VERSION 5.7 ;
BUSBITCHARS "[]" ;
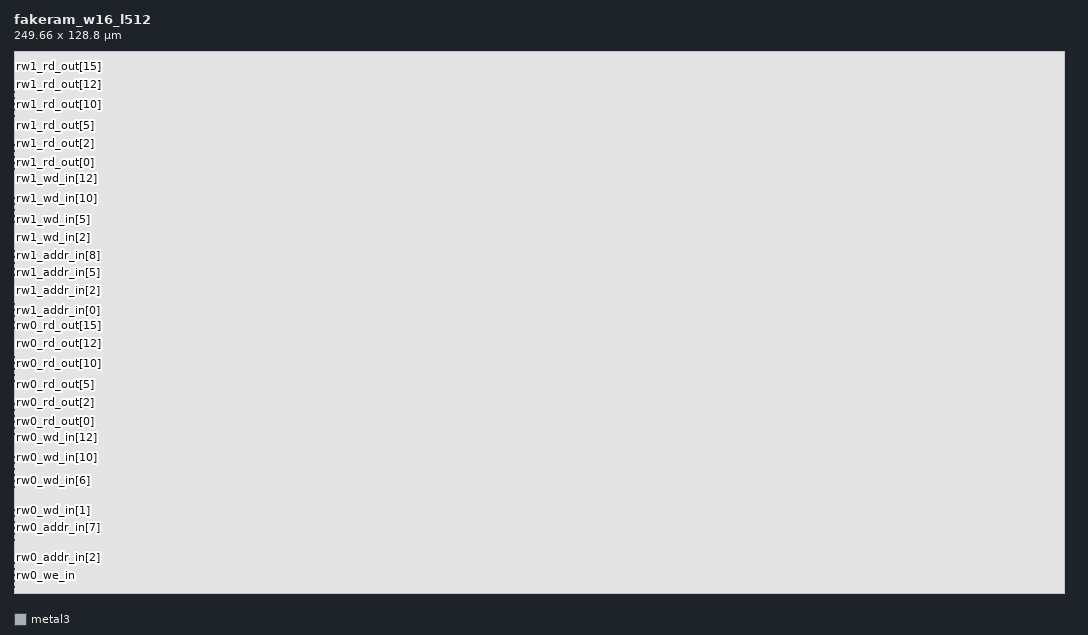
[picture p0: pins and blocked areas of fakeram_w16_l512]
MACRO fakeram_w16_l512
  FOREIGN fakeram_w16_l512 0 0 ;
  SYMMETRY X Y R90 ;
  SIZE 249.660 BY 128.800 ;
  CLASS BLOCK ;
  PIN rw0_clk
    DIRECTION INPUT ;
    USE SIGNAL ;
    SHAPE ABUTMENT ;
    PORT
      LAYER metal3 ;
      RECT 0.000 1.400 0.140 1.540 ;
    END
  END rw0_clk
  PIN rw0_ce_in
    DIRECTION INPUT ;
    USE SIGNAL ;
    SHAPE ABUTMENT ;
    PORT
      LAYER metal3 ;
      RECT 0.000 2.800 0.140 2.940 ;
    END
  END rw0_ce_in
  PIN rw0_we_in
    DIRECTION INPUT ;
    USE SIGNAL ;
    SHAPE ABUTMENT ;
    PORT
      LAYER metal3 ;
      RECT 0.000 4.200 0.140 4.340 ;
    END
  END rw0_we_in
  PIN rw0_addr_in[0]
    DIRECTION INPUT ;
    USE SIGNAL ;
    SHAPE ABUTMENT ;
    PORT
      LAYER metal3 ;
      RECT 0.000 5.600 0.140 5.740 ;
    END
  END rw0_addr_in[0]
  PIN rw0_addr_in[1]
    DIRECTION INPUT ;
    USE SIGNAL ;
    SHAPE ABUTMENT ;
    PORT
      LAYER metal3 ;
      RECT 0.000 7.000 0.140 7.140 ;
    END
  END rw0_addr_in[1]
  PIN rw0_addr_in[2]
    DIRECTION INPUT ;
    USE SIGNAL ;
    SHAPE ABUTMENT ;
    PORT
      LAYER metal3 ;
      RECT 0.000 8.400 0.140 8.540 ;
    END
  END rw0_addr_in[2]
  PIN rw0_addr_in[3]
    DIRECTION INPUT ;
    USE SIGNAL ;
    SHAPE ABUTMENT ;
    PORT
      LAYER metal3 ;
      RECT 0.000 9.800 0.140 9.940 ;
    END
  END rw0_addr_in[3]
  PIN rw0_addr_in[4]
    DIRECTION INPUT ;
    USE SIGNAL ;
    SHAPE ABUTMENT ;
    PORT
      LAYER metal3 ;
      RECT 0.000 11.200 0.140 11.340 ;
    END
  END rw0_addr_in[4]
  PIN rw0_addr_in[5]
    DIRECTION INPUT ;
    USE SIGNAL ;
    SHAPE ABUTMENT ;
    PORT
      LAYER metal3 ;
      RECT 0.000 12.600 0.140 12.740 ;
    END
  END rw0_addr_in[5]
  PIN rw0_addr_in[6]
    DIRECTION INPUT ;
    USE SIGNAL ;
    SHAPE ABUTMENT ;
    PORT
      LAYER metal3 ;
      RECT 0.000 14.000 0.140 14.140 ;
    END
  END rw0_addr_in[6]
  PIN rw0_addr_in[7]
    DIRECTION INPUT ;
    USE SIGNAL ;
    SHAPE ABUTMENT ;
    PORT
      LAYER metal3 ;
      RECT 0.000 15.400 0.140 15.540 ;
    END
  END rw0_addr_in[7]
  PIN rw0_addr_in[8]
    DIRECTION INPUT ;
    USE SIGNAL ;
    SHAPE ABUTMENT ;
    PORT
      LAYER metal3 ;
      RECT 0.000 16.800 0.140 16.940 ;
    END
  END rw0_addr_in[8]
  PIN rw0_wd_in[0]
    DIRECTION INPUT ;
    USE SIGNAL ;
    SHAPE ABUTMENT ;
    PORT
      LAYER metal3 ;
      RECT 0.000 18.200 0.140 18.340 ;
    END
  END rw0_wd_in[0]
  PIN rw0_wd_in[1]
    DIRECTION INPUT ;
    USE SIGNAL ;
    SHAPE ABUTMENT ;
    PORT
      LAYER metal3 ;
      RECT 0.000 19.600 0.140 19.740 ;
    END
  END rw0_wd_in[1]
  PIN rw0_wd_in[2]
    DIRECTION INPUT ;
    USE SIGNAL ;
    SHAPE ABUTMENT ;
    PORT
      LAYER metal3 ;
      RECT 0.000 21.000 0.140 21.140 ;
    END
  END rw0_wd_in[2]
  PIN rw0_wd_in[3]
    DIRECTION INPUT ;
    USE SIGNAL ;
    SHAPE ABUTMENT ;
    PORT
      LAYER metal3 ;
      RECT 0.000 22.400 0.140 22.540 ;
    END
  END rw0_wd_in[3]
  PIN rw0_wd_in[4]
    DIRECTION INPUT ;
    USE SIGNAL ;
    SHAPE ABUTMENT ;
    PORT
      LAYER metal3 ;
      RECT 0.000 23.800 0.140 23.940 ;
    END
  END rw0_wd_in[4]
  PIN rw0_wd_in[5]
    DIRECTION INPUT ;
    USE SIGNAL ;
    SHAPE ABUTMENT ;
    PORT
      LAYER metal3 ;
      RECT 0.000 25.200 0.140 25.340 ;
    END
  END rw0_wd_in[5]
  PIN rw0_wd_in[6]
    DIRECTION INPUT ;
    USE SIGNAL ;
    SHAPE ABUTMENT ;
    PORT
      LAYER metal3 ;
      RECT 0.000 26.600 0.140 26.740 ;
    END
  END rw0_wd_in[6]
  PIN rw0_wd_in[7]
    DIRECTION INPUT ;
    USE SIGNAL ;
    SHAPE ABUTMENT ;
    PORT
      LAYER metal3 ;
      RECT 0.000 28.000 0.140 28.140 ;
    END
  END rw0_wd_in[7]
  PIN rw0_wd_in[8]
    DIRECTION INPUT ;
    USE SIGNAL ;
    SHAPE ABUTMENT ;
    PORT
      LAYER metal3 ;
      RECT 0.000 29.400 0.140 29.540 ;
    END
  END rw0_wd_in[8]
  PIN rw0_wd_in[9]
    DIRECTION INPUT ;
    USE SIGNAL ;
    SHAPE ABUTMENT ;
    PORT
      LAYER metal3 ;
      RECT 0.000 30.800 0.140 30.940 ;
    END
  END rw0_wd_in[9]
  PIN rw0_wd_in[10]
    DIRECTION INPUT ;
    USE SIGNAL ;
    SHAPE ABUTMENT ;
    PORT
      LAYER metal3 ;
      RECT 0.000 32.200 0.140 32.340 ;
    END
  END rw0_wd_in[10]
  PIN rw0_wd_in[11]
    DIRECTION INPUT ;
    USE SIGNAL ;
    SHAPE ABUTMENT ;
    PORT
      LAYER metal3 ;
      RECT 0.000 33.600 0.140 33.740 ;
    END
  END rw0_wd_in[11]
  PIN rw0_wd_in[12]
    DIRECTION INPUT ;
    USE SIGNAL ;
    SHAPE ABUTMENT ;
    PORT
      LAYER metal3 ;
      RECT 0.000 35.000 0.140 35.140 ;
    END
  END rw0_wd_in[12]
  PIN rw0_wd_in[13]
    DIRECTION INPUT ;
    USE SIGNAL ;
    SHAPE ABUTMENT ;
    PORT
      LAYER metal3 ;
      RECT 0.000 36.400 0.140 36.540 ;
    END
  END rw0_wd_in[13]
  PIN rw0_wd_in[14]
    DIRECTION INPUT ;
    USE SIGNAL ;
    SHAPE ABUTMENT ;
    PORT
      LAYER metal3 ;
      RECT 0.000 37.800 0.140 37.940 ;
    END
  END rw0_wd_in[14]
  PIN rw0_wd_in[15]
    DIRECTION INPUT ;
    USE SIGNAL ;
    SHAPE ABUTMENT ;
    PORT
      LAYER metal3 ;
      RECT 0.000 39.200 0.140 39.340 ;
    END
  END rw0_wd_in[15]
  PIN rw0_rd_out[0]
    DIRECTION OUTPUT ;
    USE SIGNAL ;
    SHAPE ABUTMENT ;
    PORT
      LAYER metal3 ;
      RECT 0.000 40.600 0.140 40.740 ;
    END
  END rw0_rd_out[0]
  PIN rw0_rd_out[1]
    DIRECTION OUTPUT ;
    USE SIGNAL ;
    SHAPE ABUTMENT ;
    PORT
      LAYER metal3 ;
      RECT 0.000 42.000 0.140 42.140 ;
    END
  END rw0_rd_out[1]
  PIN rw0_rd_out[2]
    DIRECTION OUTPUT ;
    USE SIGNAL ;
    SHAPE ABUTMENT ;
    PORT
      LAYER metal3 ;
      RECT 0.000 43.400 0.140 43.540 ;
    END
  END rw0_rd_out[2]
  PIN rw0_rd_out[3]
    DIRECTION OUTPUT ;
    USE SIGNAL ;
    SHAPE ABUTMENT ;
    PORT
      LAYER metal3 ;
      RECT 0.000 44.800 0.140 44.940 ;
    END
  END rw0_rd_out[3]
  PIN rw0_rd_out[4]
    DIRECTION OUTPUT ;
    USE SIGNAL ;
    SHAPE ABUTMENT ;
    PORT
      LAYER metal3 ;
      RECT 0.000 46.200 0.140 46.340 ;
    END
  END rw0_rd_out[4]
  PIN rw0_rd_out[5]
    DIRECTION OUTPUT ;
    USE SIGNAL ;
    SHAPE ABUTMENT ;
    PORT
      LAYER metal3 ;
      RECT 0.000 47.600 0.140 47.740 ;
    END
  END rw0_rd_out[5]
  PIN rw0_rd_out[6]
    DIRECTION OUTPUT ;
    USE SIGNAL ;
    SHAPE ABUTMENT ;
    PORT
      LAYER metal3 ;
      RECT 0.000 49.000 0.140 49.140 ;
    END
  END rw0_rd_out[6]
  PIN rw0_rd_out[7]
    DIRECTION OUTPUT ;
    USE SIGNAL ;
    SHAPE ABUTMENT ;
    PORT
      LAYER metal3 ;
      RECT 0.000 50.400 0.140 50.540 ;
    END
  END rw0_rd_out[7]
  PIN rw0_rd_out[8]
    DIRECTION OUTPUT ;
    USE SIGNAL ;
    SHAPE ABUTMENT ;
    PORT
      LAYER metal3 ;
      RECT 0.000 51.800 0.140 51.940 ;
    END
  END rw0_rd_out[8]
  PIN rw0_rd_out[9]
    DIRECTION OUTPUT ;
    USE SIGNAL ;
    SHAPE ABUTMENT ;
    PORT
      LAYER metal3 ;
      RECT 0.000 53.200 0.140 53.340 ;
    END
  END rw0_rd_out[9]
  PIN rw0_rd_out[10]
    DIRECTION OUTPUT ;
    USE SIGNAL ;
    SHAPE ABUTMENT ;
    PORT
      LAYER metal3 ;
      RECT 0.000 54.600 0.140 54.740 ;
    END
  END rw0_rd_out[10]
  PIN rw0_rd_out[11]
    DIRECTION OUTPUT ;
    USE SIGNAL ;
    SHAPE ABUTMENT ;
    PORT
      LAYER metal3 ;
      RECT 0.000 56.000 0.140 56.140 ;
    END
  END rw0_rd_out[11]
  PIN rw0_rd_out[12]
    DIRECTION OUTPUT ;
    USE SIGNAL ;
    SHAPE ABUTMENT ;
    PORT
      LAYER metal3 ;
      RECT 0.000 57.400 0.140 57.540 ;
    END
  END rw0_rd_out[12]
  PIN rw0_rd_out[13]
    DIRECTION OUTPUT ;
    USE SIGNAL ;
    SHAPE ABUTMENT ;
    PORT
      LAYER metal3 ;
      RECT 0.000 58.800 0.140 58.940 ;
    END
  END rw0_rd_out[13]
  PIN rw0_rd_out[14]
    DIRECTION OUTPUT ;
    USE SIGNAL ;
    SHAPE ABUTMENT ;
    PORT
      LAYER metal3 ;
      RECT 0.000 60.200 0.140 60.340 ;
    END
  END rw0_rd_out[14]
  PIN rw0_rd_out[15]
    DIRECTION OUTPUT ;
    USE SIGNAL ;
    SHAPE ABUTMENT ;
    PORT
      LAYER metal3 ;
      RECT 0.000 61.600 0.140 61.740 ;
    END
  END rw0_rd_out[15]
  PIN rw1_clk
    DIRECTION INPUT ;
    USE SIGNAL ;
    SHAPE ABUTMENT ;
    PORT
      LAYER metal3 ;
      RECT 0.000 63.000 0.140 63.140 ;
    END
  END rw1_clk
  PIN rw1_ce_in
    DIRECTION INPUT ;
    USE SIGNAL ;
    SHAPE ABUTMENT ;
    PORT
      LAYER metal3 ;
      RECT 0.000 64.400 0.140 64.540 ;
    END
  END rw1_ce_in
  PIN rw1_we_in
    DIRECTION INPUT ;
    USE SIGNAL ;
    SHAPE ABUTMENT ;
    PORT
      LAYER metal3 ;
      RECT 0.000 65.800 0.140 65.940 ;
    END
  END rw1_we_in
  PIN rw1_addr_in[0]
    DIRECTION INPUT ;
    USE SIGNAL ;
    SHAPE ABUTMENT ;
    PORT
      LAYER metal3 ;
      RECT 0.000 67.200 0.140 67.340 ;
    END
  END rw1_addr_in[0]
  PIN rw1_addr_in[1]
    DIRECTION INPUT ;
    USE SIGNAL ;
    SHAPE ABUTMENT ;
    PORT
      LAYER metal3 ;
      RECT 0.000 68.600 0.140 68.740 ;
    END
  END rw1_addr_in[1]
  PIN rw1_addr_in[2]
    DIRECTION INPUT ;
    USE SIGNAL ;
    SHAPE ABUTMENT ;
    PORT
      LAYER metal3 ;
      RECT 0.000 70.000 0.140 70.140 ;
    END
  END rw1_addr_in[2]
  PIN rw1_addr_in[3]
    DIRECTION INPUT ;
    USE SIGNAL ;
    SHAPE ABUTMENT ;
    PORT
      LAYER metal3 ;
      RECT 0.000 71.400 0.140 71.540 ;
    END
  END rw1_addr_in[3]
  PIN rw1_addr_in[4]
    DIRECTION INPUT ;
    USE SIGNAL ;
    SHAPE ABUTMENT ;
    PORT
      LAYER metal3 ;
      RECT 0.000 72.800 0.140 72.940 ;
    END
  END rw1_addr_in[4]
  PIN rw1_addr_in[5]
    DIRECTION INPUT ;
    USE SIGNAL ;
    SHAPE ABUTMENT ;
    PORT
      LAYER metal3 ;
      RECT 0.000 74.200 0.140 74.340 ;
    END
  END rw1_addr_in[5]
  PIN rw1_addr_in[6]
    DIRECTION INPUT ;
    USE SIGNAL ;
    SHAPE ABUTMENT ;
    PORT
      LAYER metal3 ;
      RECT 0.000 75.600 0.140 75.740 ;
    END
  END rw1_addr_in[6]
  PIN rw1_addr_in[7]
    DIRECTION INPUT ;
    USE SIGNAL ;
    SHAPE ABUTMENT ;
    PORT
      LAYER metal3 ;
      RECT 0.000 77.000 0.140 77.140 ;
    END
  END rw1_addr_in[7]
  PIN rw1_addr_in[8]
    DIRECTION INPUT ;
    USE SIGNAL ;
    SHAPE ABUTMENT ;
    PORT
      LAYER metal3 ;
      RECT 0.000 78.400 0.140 78.540 ;
    END
  END rw1_addr_in[8]
  PIN rw1_wd_in[0]
    DIRECTION INPUT ;
    USE SIGNAL ;
    SHAPE ABUTMENT ;
    PORT
      LAYER metal3 ;
      RECT 0.000 79.800 0.140 79.940 ;
    END
  END rw1_wd_in[0]
  PIN rw1_wd_in[1]
    DIRECTION INPUT ;
    USE SIGNAL ;
    SHAPE ABUTMENT ;
    PORT
      LAYER metal3 ;
      RECT 0.000 81.200 0.140 81.340 ;
    END
  END rw1_wd_in[1]
  PIN rw1_wd_in[2]
    DIRECTION INPUT ;
    USE SIGNAL ;
    SHAPE ABUTMENT ;
    PORT
      LAYER metal3 ;
      RECT 0.000 82.600 0.140 82.740 ;
    END
  END rw1_wd_in[2]
  PIN rw1_wd_in[3]
    DIRECTION INPUT ;
    USE SIGNAL ;
    SHAPE ABUTMENT ;
    PORT
      LAYER metal3 ;
      RECT 0.000 84.000 0.140 84.140 ;
    END
  END rw1_wd_in[3]
  PIN rw1_wd_in[4]
    DIRECTION INPUT ;
    USE SIGNAL ;
    SHAPE ABUTMENT ;
    PORT
      LAYER metal3 ;
      RECT 0.000 85.400 0.140 85.540 ;
    END
  END rw1_wd_in[4]
  PIN rw1_wd_in[5]
    DIRECTION INPUT ;
    USE SIGNAL ;
    SHAPE ABUTMENT ;
    PORT
      LAYER metal3 ;
      RECT 0.000 86.800 0.140 86.940 ;
    END
  END rw1_wd_in[5]
  PIN rw1_wd_in[6]
    DIRECTION INPUT ;
    USE SIGNAL ;
    SHAPE ABUTMENT ;
    PORT
      LAYER metal3 ;
      RECT 0.000 88.200 0.140 88.340 ;
    END
  END rw1_wd_in[6]
  PIN rw1_wd_in[7]
    DIRECTION INPUT ;
    USE SIGNAL ;
    SHAPE ABUTMENT ;
    PORT
      LAYER metal3 ;
      RECT 0.000 89.600 0.140 89.740 ;
    END
  END rw1_wd_in[7]
  PIN rw1_wd_in[8]
    DIRECTION INPUT ;
    USE SIGNAL ;
    SHAPE ABUTMENT ;
    PORT
      LAYER metal3 ;
      RECT 0.000 91.000 0.140 91.140 ;
    END
  END rw1_wd_in[8]
  PIN rw1_wd_in[9]
    DIRECTION INPUT ;
    USE SIGNAL ;
    SHAPE ABUTMENT ;
    PORT
      LAYER metal3 ;
      RECT 0.000 92.400 0.140 92.540 ;
    END
  END rw1_wd_in[9]
  PIN rw1_wd_in[10]
    DIRECTION INPUT ;
    USE SIGNAL ;
    SHAPE ABUTMENT ;
    PORT
      LAYER metal3 ;
      RECT 0.000 93.800 0.140 93.940 ;
    END
  END rw1_wd_in[10]
  PIN rw1_wd_in[11]
    DIRECTION INPUT ;
    USE SIGNAL ;
    SHAPE ABUTMENT ;
    PORT
      LAYER metal3 ;
      RECT 0.000 95.200 0.140 95.340 ;
    END
  END rw1_wd_in[11]
  PIN rw1_wd_in[12]
    DIRECTION INPUT ;
    USE SIGNAL ;
    SHAPE ABUTMENT ;
    PORT
      LAYER metal3 ;
      RECT 0.000 96.600 0.140 96.740 ;
    END
  END rw1_wd_in[12]
  PIN rw1_wd_in[13]
    DIRECTION INPUT ;
    USE SIGNAL ;
    SHAPE ABUTMENT ;
    PORT
      LAYER metal3 ;
      RECT 0.000 98.000 0.140 98.140 ;
    END
  END rw1_wd_in[13]
  PIN rw1_wd_in[14]
    DIRECTION INPUT ;
    USE SIGNAL ;
    SHAPE ABUTMENT ;
    PORT
      LAYER metal3 ;
      RECT 0.000 99.400 0.140 99.540 ;
    END
  END rw1_wd_in[14]
  PIN rw1_wd_in[15]
    DIRECTION INPUT ;
    USE SIGNAL ;
    SHAPE ABUTMENT ;
    PORT
      LAYER metal3 ;
      RECT 0.000 100.800 0.140 100.940 ;
    END
  END rw1_wd_in[15]
  PIN rw1_rd_out[0]
    DIRECTION OUTPUT ;
    USE SIGNAL ;
    SHAPE ABUTMENT ;
    PORT
      LAYER metal3 ;
      RECT 0.000 102.200 0.140 102.340 ;
    END
  END rw1_rd_out[0]
  PIN rw1_rd_out[1]
    DIRECTION OUTPUT ;
    USE SIGNAL ;
    SHAPE ABUTMENT ;
    PORT
      LAYER metal3 ;
      RECT 0.000 103.600 0.140 103.740 ;
    END
  END rw1_rd_out[1]
  PIN rw1_rd_out[2]
    DIRECTION OUTPUT ;
    USE SIGNAL ;
    SHAPE ABUTMENT ;
    PORT
      LAYER metal3 ;
      RECT 0.000 105.000 0.140 105.140 ;
    END
  END rw1_rd_out[2]
  PIN rw1_rd_out[3]
    DIRECTION OUTPUT ;
    USE SIGNAL ;
    SHAPE ABUTMENT ;
    PORT
      LAYER metal3 ;
      RECT 0.000 106.400 0.140 106.540 ;
    END
  END rw1_rd_out[3]
  PIN rw1_rd_out[4]
    DIRECTION OUTPUT ;
    USE SIGNAL ;
    SHAPE ABUTMENT ;
    PORT
      LAYER metal3 ;
      RECT 0.000 107.800 0.140 107.940 ;
    END
  END rw1_rd_out[4]
  PIN rw1_rd_out[5]
    DIRECTION OUTPUT ;
    USE SIGNAL ;
    SHAPE ABUTMENT ;
    PORT
      LAYER metal3 ;
      RECT 0.000 109.200 0.140 109.340 ;
    END
  END rw1_rd_out[5]
  PIN rw1_rd_out[6]
    DIRECTION OUTPUT ;
    USE SIGNAL ;
    SHAPE ABUTMENT ;
    PORT
      LAYER metal3 ;
      RECT 0.000 110.600 0.140 110.740 ;
    END
  END rw1_rd_out[6]
  PIN rw1_rd_out[7]
    DIRECTION OUTPUT ;
    USE SIGNAL ;
    SHAPE ABUTMENT ;
    PORT
      LAYER metal3 ;
      RECT 0.000 112.000 0.140 112.140 ;
    END
  END rw1_rd_out[7]
  PIN rw1_rd_out[8]
    DIRECTION OUTPUT ;
    USE SIGNAL ;
    SHAPE ABUTMENT ;
    PORT
      LAYER metal3 ;
      RECT 0.000 113.400 0.140 113.540 ;
    END
  END rw1_rd_out[8]
  PIN rw1_rd_out[9]
    DIRECTION OUTPUT ;
    USE SIGNAL ;
    SHAPE ABUTMENT ;
    PORT
      LAYER metal3 ;
      RECT 0.000 114.800 0.140 114.940 ;
    END
  END rw1_rd_out[9]
  PIN rw1_rd_out[10]
    DIRECTION OUTPUT ;
    USE SIGNAL ;
    SHAPE ABUTMENT ;
    PORT
      LAYER metal3 ;
      RECT 0.000 116.200 0.140 116.340 ;
    END
  END rw1_rd_out[10]
  PIN rw1_rd_out[11]
    DIRECTION OUTPUT ;
    USE SIGNAL ;
    SHAPE ABUTMENT ;
    PORT
      LAYER metal3 ;
      RECT 0.000 117.600 0.140 117.740 ;
    END
  END rw1_rd_out[11]
  PIN rw1_rd_out[12]
    DIRECTION OUTPUT ;
    USE SIGNAL ;
    SHAPE ABUTMENT ;
    PORT
      LAYER metal3 ;
      RECT 0.000 119.000 0.140 119.140 ;
    END
  END rw1_rd_out[12]
  PIN rw1_rd_out[13]
    DIRECTION OUTPUT ;
    USE SIGNAL ;
    SHAPE ABUTMENT ;
    PORT
      LAYER metal3 ;
      RECT 0.000 120.400 0.140 120.540 ;
    END
  END rw1_rd_out[13]
  PIN rw1_rd_out[14]
    DIRECTION OUTPUT ;
    USE SIGNAL ;
    SHAPE ABUTMENT ;
    PORT
      LAYER metal3 ;
      RECT 0.000 121.800 0.140 121.940 ;
    END
  END rw1_rd_out[14]
  PIN rw1_rd_out[15]
    DIRECTION OUTPUT ;
    USE SIGNAL ;
    SHAPE ABUTMENT ;
    PORT
      LAYER metal3 ;
      RECT 0.000 123.200 0.140 123.340 ;
    END
  END rw1_rd_out[15]
  OBS
    LAYER metal1 ;
      RECT 0.000 0.000 249.660 128.800 ;
    LAYER metal2 ;
      RECT 0.000 0.000 249.660 128.800 ;
    LAYER metal3 ;
      RECT 0.000 0.000 249.660 128.800 ;
    LAYER metal4 ;
      RECT 0.000 0.000 249.660 128.800 ;
  END
END fakeram_w16_l512
END LIBRARY
